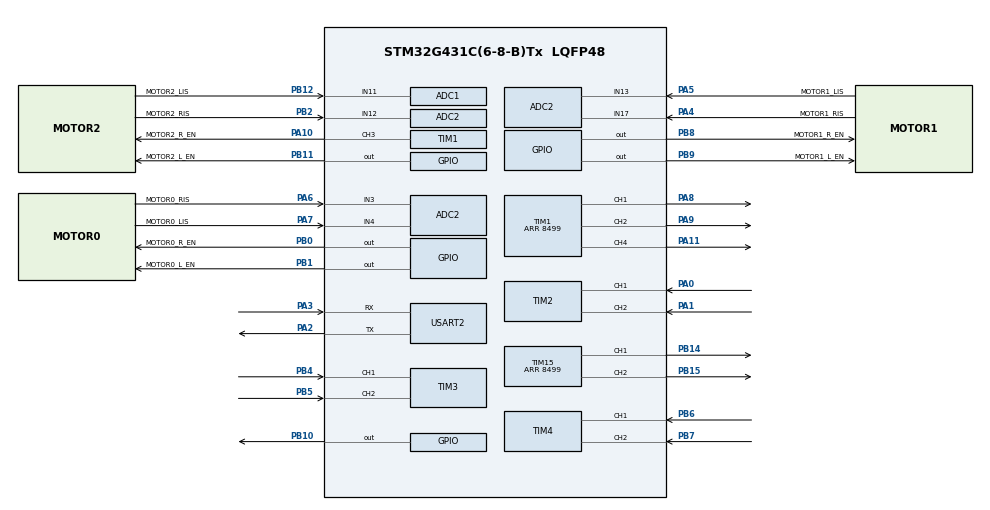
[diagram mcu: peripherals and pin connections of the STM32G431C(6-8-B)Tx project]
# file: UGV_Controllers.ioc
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ADC1.Channel-0\#ChannelRegularConversion=ADC_CHANNEL_11
ADC1.NbrOfConversionFlag=1
ADC1.OffsetNumber-0\#ChannelRegularConversion=ADC_OFFSET_NONE
ADC1.Rank-0\#ChannelRegularConversion=1
ADC1.SamplingTime-0\#ChannelRegularConversion=ADC_SAMPLETIME_2CYCLES_5
ADC1.master=1
ADC2.Channel-0\#ChannelRegularConversion=ADC_CHANNEL_3
ADC2.Channel-1\#ChannelRegularConversion=ADC_CHANNEL_4
ADC2.Channel-2\#ChannelRegularConversion=ADC_CHANNEL_12
ADC2.Channel-3\#ChannelRegularConversion=ADC_CHANNEL_13
ADC2.Channel-4\#ChannelRegularConversion=ADC_CHANNEL_17
ADC2.NbrOfConversion=5
ADC2.NbrOfConversionFlag=1
ADC2.OffsetNumber-0\#ChannelRegularConversion=ADC_OFFSET_NONE
ADC2.OffsetNumber-1\#ChannelRegularConversion=ADC_OFFSET_NONE
ADC2.OffsetNumber-2\#ChannelRegularConversion=ADC_OFFSET_NONE
ADC2.OffsetNumber-3\#ChannelRegularConversion=ADC_OFFSET_NONE
ADC2.OffsetNumber-4\#ChannelRegularConversion=ADC_OFFSET_NONE
ADC2.Rank-0\#ChannelRegularConversion=1
ADC2.Rank-1\#ChannelRegularConversion=2
ADC2.Rank-2\#ChannelRegularConversion=3
ADC2.Rank-3\#ChannelRegularConversion=4
ADC2.Rank-4\#ChannelRegularConversion=5
ADC2.SamplingTime-0\#ChannelRegularConversion=ADC_SAMPLETIME_2CYCLES_5
ADC2.SamplingTime-1\#ChannelRegularConversion=ADC_SAMPLETIME_2CYCLES_5
ADC2.SamplingTime-2\#ChannelRegularConversion=ADC_SAMPLETIME_2CYCLES_5
ADC2.SamplingTime-3\#ChannelRegularConversion=ADC_SAMPLETIME_2CYCLES_5
ADC2.SamplingTime-4\#ChannelRegularConversion=ADC_SAMPLETIME_2CYCLES_5
Mcu.Family=STM32G4
Mcu.Name=STM32G431C(6-8-B)Tx
Mcu.Package=LQFP48
NVIC.PriorityGroup=NVIC_PRIORITYGROUP_4
NVIC.USART2_IRQn=true\:5\:0\:false\:false\:true\:false\:true\:false
PA0.Signal=S_TIM2_CH1
PA1.Signal=S_TIM2_CH2
PA10.GPIO_Label=MOTOR2_R_EN
PA10.Signal=S_TIM1_CH3
PA11.Signal=S_TIM1_CH4
PA2.Mode=Asynchronous
PA2.Signal=USART2_TX
PA3.Mode=Asynchronous
PA3.Signal=USART2_RX
PA4.GPIO_Label=MOTOR1_RIS
PA4.Mode=IN17-Single-Ended
PA4.Signal=ADC2_IN17
PA5.GPIO_Label=MOTOR1_LIS
PA5.Mode=IN13-Single-Ended
PA5.Signal=ADC2_IN13
PA6.GPIO_Label=MOTOR0_RIS
PA6.Mode=IN3-Single-Ended
PA6.Signal=ADC2_IN3
PA7.GPIO_Label=MOTOR0_LIS
PA7.Mode=IN4-Single-Ended
PA7.Signal=ADC2_IN4
PA8.Signal=S_TIM1_CH1
PA9.Signal=S_TIM1_CH2
PB0.GPIO_Label=MOTOR0_R_EN
PB0.Signal=GPIO_Output
PB1.GPIO_Label=MOTOR0_L_EN
PB1.Signal=GPIO_Output
PB10.Signal=GPIO_Output
PB11.GPIO_Label=MOTOR2_L_EN
PB11.Signal=GPIO_Output
PB12.GPIO_Label=MOTOR2_LIS
PB12.Mode=IN11-Single-Ended
PB12.Signal=ADC1_IN11
PB14.Signal=S_TIM15_CH1
PB15.Signal=S_TIM15_CH2
PB2.GPIO_Label=MOTOR2_RIS
PB2.Mode=IN12-Single-Ended
PB2.Signal=ADC2_IN12
PB4.Signal=S_TIM3_CH1
PB5.Signal=S_TIM3_CH2
PB6.Signal=S_TIM4_CH1
PB7.Signal=S_TIM4_CH2
PB8-BOOT0.GPIO_Label=MOTOR1_R_EN
PB8-BOOT0.Signal=GPIO_Output
PB9.GPIO_Label=MOTOR1_L_EN
PB9.Signal=GPIO_Output
ProjectManager.HeapSize=0x200
ProjectManager.StackSize=0x400
ProjectManager.TargetToolchain=CMake
RCC.ADC12Freq_Value=170000000
RCC.AHBFreq_Value=170000000
RCC.APB1Freq_Value=170000000
RCC.APB1TimFreq_Value=170000000
RCC.APB2Freq_Value=170000000
RCC.APB2TimFreq_Value=170000000
RCC.CortexFreq_Value=170000000
RCC.EXTERNAL_CLOCK_VALUE=12288000
RCC.HCLKFreq_Value=170000000
RCC.HSE_VALUE=8000000
RCC.HSI48_VALUE=48000000
RCC.HSI_VALUE=16000000
RCC.LSE_VALUE=32768
RCC.PLLM=RCC_PLLM_DIV4
RCC.PLLN=85
RCC.PLLP=RCC_PLLP_DIV2
RCC.SYSCLKFreq_VALUE=170000000
RCC.SYSCLKSource=RCC_SYSCLKSOURCE_PLLCLK
RCC.USBFreq_Value=170000000
RCC.VCOOutputFreq_Value=340000000
SH.S_TIM15_CH1.0=TIM15_CH1,PWM Generation1 CH1
SH.S_TIM15_CH2.0=TIM15_CH2,PWM Generation2 CH2
SH.S_TIM1_CH1.0=TIM1_CH1,PWM Generation1 CH1
SH.S_TIM1_CH2.0=TIM1_CH2,PWM Generation2 CH2
SH.S_TIM1_CH3.0=TIM1_CH3,PWM Generation3 CH3
SH.S_TIM1_CH4.0=TIM1_CH4,PWM Generation4 CH4
SH.S_TIM2_CH1.0=TIM2_CH1,Encoder_Interface
SH.S_TIM2_CH2.0=TIM2_CH2,Encoder_Interface
SH.S_TIM3_CH1.0=TIM3_CH1,Encoder_Interface
SH.S_TIM3_CH2.0=TIM3_CH2,Encoder_Interface
SH.S_TIM4_CH1.0=TIM4_CH1,Encoder_Interface
SH.S_TIM4_CH2.0=TIM4_CH2,Encoder_Interface
TIM1.Channel-PWM\ Generation1\ CH1=TIM_CHANNEL_1
TIM1.Channel-PWM\ Generation2\ CH2=TIM_CHANNEL_2
TIM1.Channel-PWM\ Generation3\ CH3=TIM_CHANNEL_3
TIM1.Channel-PWM\ Generation4\ CH4=TIM_CHANNEL_4
TIM1.PeriodNoDither=8499
TIM15.Channel-PWM\ Generation1\ CH1=TIM_CHANNEL_1
TIM15.Channel-PWM\ Generation2\ CH2=TIM_CHANNEL_2
TIM15.PeriodNoDither=8499
TIM2.EncoderMode=TIM_ENCODERMODE_TI12
TIM3.EncoderMode=TIM_ENCODERMODE_TI12
TIM4.EncoderMode=TIM_ENCODERMODE_TI12
USART2.VirtualMode-Asynchronous=VM_ASYNC
VP_IWDG_VS_IWDG.Mode=IWDG_Activate
VP_SYS_VS_DBSignals.Mode=DisableDeadBatterySignals
VP_TIM15_VS_ClockSourceINT.Mode=Internal
VP_TIM1_VS_ClockSourceINT.Mode=Internal
VP_TIM6_VS_ClockSourceINT.Mode=Enable_Timer
board=custom

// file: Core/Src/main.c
/* USER CODE BEGIN Header */
/**
  ******************************************************************************
  * @file           : main.c
  * @brief          : Main program body
  ******************************************************************************
  * @attention
  *
  * Copyright (c) 2026 STMicroelectronics.
  * All rights reserved.
  *
  * This software is licensed under terms that can be found in the LICENSE file
  * in the root directory of this software component.
  * If no LICENSE file comes with this software, it is provided AS-IS.
  *
  ******************************************************************************
  */
/* USER CODE END Header */
#include "main.h"

/* USER CODE BEGIN Includes */
#include "app_main.h"
/* USER CODE END Includes */

ADC_HandleTypeDef hadc1;
ADC_HandleTypeDef hadc2;

IWDG_HandleTypeDef hiwdg;

TIM_HandleTypeDef htim1;
TIM_HandleTypeDef htim2;
TIM_HandleTypeDef htim3;
TIM_HandleTypeDef htim4;
TIM_HandleTypeDef htim6;
TIM_HandleTypeDef htim15;

UART_HandleTypeDef huart2;

void SystemClock_Config(void);
static void MX_GPIO_Init(void);
static void MX_TIM6_Init(void);
static void MX_ADC2_Init(void);
static void MX_TIM1_Init(void);
static void MX_IWDG_Init(void);
static void MX_TIM2_Init(void);
static void MX_TIM3_Init(void);
static void MX_TIM4_Init(void);
static void MX_TIM15_Init(void);
static void MX_USART2_UART_Init(void);
static void MX_ADC1_Init(void);

int main(void)
{

  /* MCU Configuration--------------------------------------------------------*/

  /* Reset of all peripherals, Initializes the Flash interface and the Systick. */
  HAL_Init();

  /* Configure the system clock */
  SystemClock_Config();

  /* Initialize all configured peripherals */
  MX_GPIO_Init();
  MX_TIM6_Init();
  MX_ADC2_Init();
  MX_TIM1_Init();
  MX_IWDG_Init();
  MX_TIM2_Init();
  MX_TIM3_Init();
  MX_TIM4_Init();
  MX_TIM15_Init();
  MX_USART2_UART_Init();
  MX_ADC1_Init();
  /* USER CODE BEGIN 2 */
  app_main_init();
  /* USER CODE END 2 */

  /* Infinite loop */
  /* USER CODE BEGIN WHILE */
  while (1)
  {
    app_main_run();
    /* USER CODE END WHILE */

  }
}

void SystemClock_Config(void)
{
  RCC_OscInitTypeDef RCC_OscInitStruct = {0};
  RCC_ClkInitTypeDef RCC_ClkInitStruct = {0};

  /** Configure the main internal regulator output voltage
  */
  HAL_PWREx_ControlVoltageScaling(PWR_REGULATOR_VOLTAGE_SCALE1);

  /** Initializes the RCC Oscillators according to the specified parameters
  * in the RCC_OscInitTypeDef structure.
  */
  RCC_OscInitStruct.OscillatorType = RCC_OSCILLATORTYPE_HSI|RCC_OSCILLATORTYPE_LSI;
  RCC_OscInitStruct.HSIState = RCC_HSI_ON;
  RCC_OscInitStruct.HSICalibrationValue = RCC_HSICALIBRATION_DEFAULT;
  RCC_OscInitStruct.LSIState = RCC_LSI_ON;
  RCC_OscInitStruct.PLL.PLLState = RCC_PLL_NONE;
  if (HAL_RCC_OscConfig(&RCC_OscInitStruct) != HAL_OK)
  {
    Error_Handler();
  }

  /** Initializes the CPU, AHB and APB buses clocks
  */
  RCC_ClkInitStruct.ClockType = RCC_CLOCKTYPE_HCLK|RCC_CLOCKTYPE_SYSCLK
                              |RCC_CLOCKTYPE_PCLK1|RCC_CLOCKTYPE_PCLK2;
  RCC_ClkInitStruct.SYSCLKSource = RCC_SYSCLKSOURCE_HSI;
  RCC_ClkInitStruct.AHBCLKDivider = RCC_SYSCLK_DIV1;
  RCC_ClkInitStruct.APB1CLKDivider = RCC_HCLK_DIV1;
  RCC_ClkInitStruct.APB2CLKDivider = RCC_HCLK_DIV1;

  if (HAL_RCC_ClockConfig(&RCC_ClkInitStruct, FLASH_LATENCY_0) != HAL_OK)
  {
    Error_Handler();
  }
}

static void MX_ADC1_Init(void)
{

  ADC_MultiModeTypeDef multimode = {0};
  ADC_ChannelConfTypeDef sConfig = {0};

  /** Common config
  */
  hadc1.Instance = ADC1;
  hadc1.Init.ClockPrescaler = ADC_CLOCK_SYNC_PCLK_DIV2;
  hadc1.Init.Resolution = ADC_RESOLUTION_12B;
  hadc1.Init.DataAlign = ADC_DATAALIGN_RIGHT;
  hadc1.Init.GainCompensation = 0;
  hadc1.Init.ScanConvMode = ADC_SCAN_DISABLE;
  hadc1.Init.EOCSelection = ADC_EOC_SINGLE_CONV;
  hadc1.Init.LowPowerAutoWait = DISABLE;
  hadc1.Init.ContinuousConvMode = DISABLE;
  hadc1.Init.NbrOfConversion = 1;
  hadc1.Init.DiscontinuousConvMode = DISABLE;
  hadc1.Init.ExternalTrigConv = ADC_SOFTWARE_START;
  hadc1.Init.ExternalTrigConvEdge = ADC_EXTERNALTRIGCONVEDGE_NONE;
  hadc1.Init.DMAContinuousRequests = DISABLE;
  hadc1.Init.Overrun = ADC_OVR_DATA_PRESERVED;
  hadc1.Init.OversamplingMode = DISABLE;
  if (HAL_ADC_Init(&hadc1) != HAL_OK)
  {
    Error_Handler();
  }

  /** Configure the ADC multi-mode
  */
  multimode.Mode = ADC_MODE_INDEPENDENT;
  if (HAL_ADCEx_MultiModeConfigChannel(&hadc1, &multimode) != HAL_OK)
  {
    Error_Handler();
  }

  /** Configure Regular Channel
  */
  sConfig.Channel = ADC_CHANNEL_11;
  sConfig.Rank = ADC_REGULAR_RANK_1;
  sConfig.SamplingTime = ADC_SAMPLETIME_2CYCLES_5;
  sConfig.SingleDiff = ADC_SINGLE_ENDED;
  sConfig.OffsetNumber = ADC_OFFSET_NONE;
  sConfig.Offset = 0;
  if (HAL_ADC_ConfigChannel(&hadc1, &sConfig) != HAL_OK)
  {
    Error_Handler();
  }

}

static void MX_ADC2_Init(void)
{

  ADC_ChannelConfTypeDef sConfig = {0};

  /** Common config
  */
  hadc2.Instance = ADC2;
  hadc2.Init.ClockPrescaler = ADC_CLOCK_SYNC_PCLK_DIV2;
  hadc2.Init.Resolution = ADC_RESOLUTION_12B;
  hadc2.Init.DataAlign = ADC_DATAALIGN_RIGHT;
  hadc2.Init.GainCompensation = 0;
  hadc2.Init.ScanConvMode = ADC_SCAN_ENABLE;
  hadc2.Init.EOCSelection = ADC_EOC_SINGLE_CONV;
  hadc2.Init.LowPowerAutoWait = DISABLE;
  hadc2.Init.ContinuousConvMode = DISABLE;
  hadc2.Init.NbrOfConversion = 5;
  hadc2.Init.DiscontinuousConvMode = DISABLE;
  hadc2.Init.ExternalTrigConv = ADC_SOFTWARE_START;
  hadc2.Init.ExternalTrigConvEdge = ADC_EXTERNALTRIGCONVEDGE_NONE;
  hadc2.Init.DMAContinuousRequests = DISABLE;
  hadc2.Init.Overrun = ADC_OVR_DATA_PRESERVED;
  hadc2.Init.OversamplingMode = DISABLE;
  if (HAL_ADC_Init(&hadc2) != HAL_OK)
  {
    Error_Handler();
  }

  /** Configure Regular Channel
  */
  sConfig.Channel = ADC_CHANNEL_3;
  sConfig.Rank = ADC_REGULAR_RANK_1;
  sConfig.SamplingTime = ADC_SAMPLETIME_2CYCLES_5;
  sConfig.SingleDiff = ADC_SINGLE_ENDED;
  sConfig.OffsetNumber = ADC_OFFSET_NONE;
  sConfig.Offset = 0;
  if (HAL_ADC_ConfigChannel(&hadc2, &sConfig) != HAL_OK)
  {
    Error_Handler();
  }

  /** Configure Regular Channel
  */
  sConfig.Channel = ADC_CHANNEL_4;
  sConfig.Rank = ADC_REGULAR_RANK_2;
  if (HAL_ADC_ConfigChannel(&hadc2, &sConfig) != HAL_OK)
  {
    Error_Handler();
  }

  /** Configure Regular Channel
  */
  sConfig.Channel = ADC_CHANNEL_12;
  sConfig.Rank = ADC_REGULAR_RANK_3;
  if (HAL_ADC_ConfigChannel(&hadc2, &sConfig) != HAL_OK)
  {
    Error_Handler();
  }

  /** Configure Regular Channel
  */
  sConfig.Channel = ADC_CHANNEL_13;
  sConfig.Rank = ADC_REGULAR_RANK_4;
  if (HAL_ADC_ConfigChannel(&hadc2, &sConfig) != HAL_OK)
  {
    Error_Handler();
  }

  /** Configure Regular Channel
  */
  sConfig.Channel = ADC_CHANNEL_17;
  sConfig.Rank = ADC_REGULAR_RANK_5;
  if (HAL_ADC_ConfigChannel(&hadc2, &sConfig) != HAL_OK)
  {
    Error_Handler();
  }

}

static void MX_IWDG_Init(void)
{

  hiwdg.Instance = IWDG;
  hiwdg.Init.Prescaler = IWDG_PRESCALER_4;
  hiwdg.Init.Window = 4095;
  hiwdg.Init.Reload = 4095;
  if (HAL_IWDG_Init(&hiwdg) != HAL_OK)
  {
    Error_Handler();
  }

}

static void MX_TIM1_Init(void)
{

  TIM_ClockConfigTypeDef sClockSourceConfig = {0};
  TIM_MasterConfigTypeDef sMasterConfig = {0};
  TIM_OC_InitTypeDef sConfigOC = {0};
  TIM_BreakDeadTimeConfigTypeDef sBreakDeadTimeConfig = {0};

  htim1.Instance = TIM1;
  htim1.Init.Prescaler = 0;
  htim1.Init.CounterMode = TIM_COUNTERMODE_UP;
  htim1.Init.Period = 799;
  htim1.Init.ClockDivision = TIM_CLOCKDIVISION_DIV1;
  htim1.Init.RepetitionCounter = 0;
  htim1.Init.AutoReloadPreload = TIM_AUTORELOAD_PRELOAD_DISABLE;
  if (HAL_TIM_Base_Init(&htim1) != HAL_OK)
  {
    Error_Handler();
  }
  sClockSourceConfig.ClockSource = TIM_CLOCKSOURCE_INTERNAL;
  if (HAL_TIM_ConfigClockSource(&htim1, &sClockSourceConfig) != HAL_OK)
  {
    Error_Handler();
  }
  if (HAL_TIM_PWM_Init(&htim1) != HAL_OK)
  {
    Error_Handler();
  }
  sMasterConfig.MasterOutputTrigger = TIM_TRGO_RESET;
  sMasterConfig.MasterOutputTrigger2 = TIM_TRGO2_RESET;
  sMasterConfig.MasterSlaveMode = TIM_MASTERSLAVEMODE_DISABLE;
  if (HAL_TIMEx_MasterConfigSynchronization(&htim1, &sMasterConfig) != HAL_OK)
  {
    Error_Handler();
  }
  sConfigOC.OCMode = TIM_OCMODE_PWM1;
  sConfigOC.Pulse = 0;
  sConfigOC.OCPolarity = TIM_OCPOLARITY_HIGH;
  sConfigOC.OCNPolarity = TIM_OCNPOLARITY_HIGH;
  sConfigOC.OCFastMode = TIM_OCFAST_DISABLE;
  sConfigOC.OCIdleState = TIM_OCIDLESTATE_RESET;
  sConfigOC.OCNIdleState = TIM_OCNIDLESTATE_RESET;
  if (HAL_TIM_PWM_ConfigChannel(&htim1, &sConfigOC, TIM_CHANNEL_1) != HAL_OK)
  {
    Error_Handler();
  }
  if (HAL_TIM_PWM_ConfigChannel(&htim1, &sConfigOC, TIM_CHANNEL_2) != HAL_OK)
  {
    Error_Handler();
  }
  if (HAL_TIM_PWM_ConfigChannel(&htim1, &sConfigOC, TIM_CHANNEL_3) != HAL_OK)
  {
    Error_Handler();
  }
  if (HAL_TIM_PWM_ConfigChannel(&htim1, &sConfigOC, TIM_CHANNEL_4) != HAL_OK)
  {
    Error_Handler();
  }
  sBreakDeadTimeConfig.OffStateRunMode = TIM_OSSR_DISABLE;
  sBreakDeadTimeConfig.OffStateIDLEMode = TIM_OSSI_DISABLE;
  sBreakDeadTimeConfig.LockLevel = TIM_LOCKLEVEL_OFF;
  sBreakDeadTimeConfig.DeadTime = 0;
  sBreakDeadTimeConfig.BreakState = TIM_BREAK_DISABLE;
  sBreakDeadTimeConfig.BreakPolarity = TIM_BREAKPOLARITY_HIGH;
  sBreakDeadTimeConfig.BreakFilter = 0;
  sBreakDeadTimeConfig.BreakAFMode = TIM_BREAK_AFMODE_INPUT;
  sBreakDeadTimeConfig.Break2State = TIM_BREAK2_DISABLE;
  sBreakDeadTimeConfig.Break2Polarity = TIM_BREAK2POLARITY_HIGH;
  sBreakDeadTimeConfig.Break2Filter = 0;
  sBreakDeadTimeConfig.Break2AFMode = TIM_BREAK_AFMODE_INPUT;
  sBreakDeadTimeConfig.AutomaticOutput = TIM_AUTOMATICOUTPUT_DISABLE;
  if (HAL_TIMEx_ConfigBreakDeadTime(&htim1, &sBreakDeadTimeConfig) != HAL_OK)
  {
    Error_Handler();
  }
  HAL_TIM_MspPostInit(&htim1);

}

static void MX_TIM2_Init(void)
{

  TIM_Encoder_InitTypeDef sConfig = {0};
  TIM_MasterConfigTypeDef sMasterConfig = {0};

  htim2.Instance = TIM2;
  htim2.Init.Prescaler = 0;
  htim2.Init.CounterMode = TIM_COUNTERMODE_UP;
  htim2.Init.Period = 4294967295;
  htim2.Init.ClockDivision = TIM_CLOCKDIVISION_DIV1;
  htim2.Init.AutoReloadPreload = TIM_AUTORELOAD_PRELOAD_DISABLE;
  sConfig.EncoderMode = TIM_ENCODERMODE_TI12;
  sConfig.IC1Polarity = TIM_ICPOLARITY_RISING;
  sConfig.IC1Selection = TIM_ICSELECTION_DIRECTTI;
  sConfig.IC1Prescaler = TIM_ICPSC_DIV1;
  sConfig.IC1Filter = 0;
  sConfig.IC2Polarity = TIM_ICPOLARITY_RISING;
  sConfig.IC2Selection = TIM_ICSELECTION_DIRECTTI;
  sConfig.IC2Prescaler = TIM_ICPSC_DIV1;
  sConfig.IC2Filter = 0;
  if (HAL_TIM_Encoder_Init(&htim2, &sConfig) != HAL_OK)
  {
    Error_Handler();
  }
  sMasterConfig.MasterOutputTrigger = TIM_TRGO_RESET;
  sMasterConfig.MasterSlaveMode = TIM_MASTERSLAVEMODE_DISABLE;
  if (HAL_TIMEx_MasterConfigSynchronization(&htim2, &sMasterConfig) != HAL_OK)
  {
    Error_Handler();
  }

}

static void MX_TIM3_Init(void)
{

  TIM_Encoder_InitTypeDef sConfig = {0};
  TIM_MasterConfigTypeDef sMasterConfig = {0};

  htim3.Instance = TIM3;
  htim3.Init.Prescaler = 0;
  htim3.Init.CounterMode = TIM_COUNTERMODE_UP;
  htim3.Init.Period = 65535;
  htim3.Init.ClockDivision = TIM_CLOCKDIVISION_DIV1;
  htim3.Init.AutoReloadPreload = TIM_AUTORELOAD_PRELOAD_DISABLE;
  sConfig.EncoderMode = TIM_ENCODERMODE_TI12;
  sConfig.IC1Polarity = TIM_ICPOLARITY_RISING;
  sConfig.IC1Selection = TIM_ICSELECTION_DIRECTTI;
  sConfig.IC1Prescaler = TIM_ICPSC_DIV1;
  sConfig.IC1Filter = 0;
  sConfig.IC2Polarity = TIM_ICPOLARITY_RISING;
  sConfig.IC2Selection = TIM_ICSELECTION_DIRECTTI;
  sConfig.IC2Prescaler = TIM_ICPSC_DIV1;
  sConfig.IC2Filter = 0;
  if (HAL_TIM_Encoder_Init(&htim3, &sConfig) != HAL_OK)
  {
    Error_Handler();
  }
  sMasterConfig.MasterOutputTrigger = TIM_TRGO_RESET;
  sMasterConfig.MasterSlaveMode = TIM_MASTERSLAVEMODE_DISABLE;
  if (HAL_TIMEx_MasterConfigSynchronization(&htim3, &sMasterConfig) != HAL_OK)
  {
    Error_Handler();
  }

}

static void MX_TIM4_Init(void)
{

  TIM_Encoder_InitTypeDef sConfig = {0};
  TIM_MasterConfigTypeDef sMasterConfig = {0};

  htim4.Instance = TIM4;
  htim4.Init.Prescaler = 0;
  htim4.Init.CounterMode = TIM_COUNTERMODE_UP;
  htim4.Init.Period = 65535;
  htim4.Init.ClockDivision = TIM_CLOCKDIVISION_DIV1;
  htim4.Init.AutoReloadPreload = TIM_AUTORELOAD_PRELOAD_DISABLE;
  sConfig.EncoderMode = TIM_ENCODERMODE_TI12;
  sConfig.IC1Polarity = TIM_ICPOLARITY_RISING;
  sConfig.IC1Selection = TIM_ICSELECTION_DIRECTTI;
  sConfig.IC1Prescaler = TIM_ICPSC_DIV1;
  sConfig.IC1Filter = 0;
  sConfig.IC2Polarity = TIM_ICPOLARITY_RISING;
  sConfig.IC2Selection = TIM_ICSELECTION_DIRECTTI;
  sConfig.IC2Prescaler = TIM_ICPSC_DIV1;
  sConfig.IC2Filter = 0;
  if (HAL_TIM_Encoder_Init(&htim4, &sConfig) != HAL_OK)
  {
    Error_Handler();
  }
  sMasterConfig.MasterOutputTrigger = TIM_TRGO_RESET;
  sMasterConfig.MasterSlaveMode = TIM_MASTERSLAVEMODE_DISABLE;
  if (HAL_TIMEx_MasterConfigSynchronization(&htim4, &sMasterConfig) != HAL_OK)
  {
    Error_Handler();
  }

}

static void MX_TIM6_Init(void)
{

  TIM_MasterConfigTypeDef sMasterConfig = {0};

  htim6.Instance = TIM6;
  htim6.Init.Prescaler = 0;
  htim6.Init.CounterMode = TIM_COUNTERMODE_UP;
  htim6.Init.Period = 65535;
  htim6.Init.AutoReloadPreload = TIM_AUTORELOAD_PRELOAD_DISABLE;
  if (HAL_TIM_Base_Init(&htim6) != HAL_OK)
  {
    Error_Handler();
  }
  sMasterConfig.MasterOutputTrigger = TIM_TRGO_RESET;
  sMasterConfig.MasterSlaveMode = TIM_MASTERSLAVEMODE_DISABLE;
  if (HAL_TIMEx_MasterConfigSynchronization(&htim6, &sMasterConfig) != HAL_OK)
  {
    Error_Handler();
  }

}

static void MX_TIM15_Init(void)
{

  TIM_ClockConfigTypeDef sClockSourceConfig = {0};
  TIM_MasterConfigTypeDef sMasterConfig = {0};
  TIM_OC_InitTypeDef sConfigOC = {0};
  TIM_BreakDeadTimeConfigTypeDef sBreakDeadTimeConfig = {0};

  htim15.Instance = TIM15;
  htim15.Init.Prescaler = 0;
  htim15.Init.CounterMode = TIM_COUNTERMODE_UP;
  htim15.Init.Period = 799;
  htim15.Init.ClockDivision = TIM_CLOCKDIVISION_DIV1;
  htim15.Init.RepetitionCounter = 0;
  htim15.Init.AutoReloadPreload = TIM_AUTORELOAD_PRELOAD_DISABLE;
  if (HAL_TIM_Base_Init(&htim15) != HAL_OK)
  {
    Error_Handler();
  }
  sClockSourceConfig.ClockSource = TIM_CLOCKSOURCE_INTERNAL;
  if (HAL_TIM_ConfigClockSource(&htim15, &sClockSourceConfig) != HAL_OK)
  {
    Error_Handler();
  }
  if (HAL_TIM_PWM_Init(&htim15) != HAL_OK)
  {
    Error_Handler();
  }
  sMasterConfig.MasterOutputTrigger = TIM_TRGO_RESET;
  sMasterConfig.MasterSlaveMode = TIM_MASTERSLAVEMODE_DISABLE;
  if (HAL_TIMEx_MasterConfigSynchronization(&htim15, &sMasterConfig) != HAL_OK)
  {
    Error_Handler();
  }
  sConfigOC.OCMode = TIM_OCMODE_PWM1;
  sConfigOC.Pulse = 0;
  sConfigOC.OCPolarity = TIM_OCPOLARITY_HIGH;
  sConfigOC.OCNPolarity = TIM_OCNPOLARITY_HIGH;
  sConfigOC.OCFastMode = TIM_OCFAST_DISABLE;
  sConfigOC.OCIdleState = TIM_OCIDLESTATE_RESET;
  sConfigOC.OCNIdleState = TIM_OCNIDLESTATE_RESET;
  if (HAL_TIM_PWM_ConfigChannel(&htim15, &sConfigOC, TIM_CHANNEL_1) != HAL_OK)
  {
    Error_Handler();
  }
  if (HAL_TIM_PWM_ConfigChannel(&htim15, &sConfigOC, TIM_CHANNEL_2) != HAL_OK)
  {
    Error_Handler();
  }
  sBreakDeadTimeConfig.OffStateRunMode = TIM_OSSR_DISABLE;
  sBreakDeadTimeConfig.OffStateIDLEMode = TIM_OSSI_DISABLE;
  sBreakDeadTimeConfig.LockLevel = TIM_LOCKLEVEL_OFF;
  sBreakDeadTimeConfig.DeadTime = 0;
  sBreakDeadTimeConfig.BreakState = TIM_BREAK_DISABLE;
  sBreakDeadTimeConfig.BreakPolarity = TIM_BREAKPOLARITY_HIGH;
  sBreakDeadTimeConfig.BreakFilter = 0;
  sBreakDeadTimeConfig.AutomaticOutput = TIM_AUTOMATICOUTPUT_DISABLE;
  if (HAL_TIMEx_ConfigBreakDeadTime(&htim15, &sBreakDeadTimeConfig) != HAL_OK)
  {
    Error_Handler();
  }
  HAL_TIM_MspPostInit(&htim15);

}

static void MX_USART2_UART_Init(void)
{

  huart2.Instance = USART2;
  huart2.Init.BaudRate = 115200;
  huart2.Init.WordLength = UART_WORDLENGTH_8B;
  huart2.Init.StopBits = UART_STOPBITS_1;
  huart2.Init.Parity = UART_PARITY_NONE;
  huart2.Init.Mode = UART_MODE_TX_RX;
  huart2.Init.HwFlowCtl = UART_HWCONTROL_NONE;
  huart2.Init.OverSampling = UART_OVERSAMPLING_16;
  huart2.Init.OneBitSampling = UART_ONE_BIT_SAMPLE_DISABLE;
  huart2.Init.ClockPrescaler = UART_PRESCALER_DIV1;
  huart2.AdvancedInit.AdvFeatureInit = UART_ADVFEATURE_NO_INIT;
  if (HAL_UART_Init(&huart2) != HAL_OK)
  {
    Error_Handler();
  }
  if (HAL_UARTEx_SetTxFifoThreshold(&huart2, UART_TXFIFO_THRESHOLD_1_8) != HAL_OK)
  {
    Error_Handler();
  }
  if (HAL_UARTEx_SetRxFifoThreshold(&huart2, UART_RXFIFO_THRESHOLD_1_8) != HAL_OK)
  {
    Error_Handler();
  }
  if (HAL_UARTEx_DisableFifoMode(&huart2) != HAL_OK)
  {
    Error_Handler();
  }

}

static void MX_GPIO_Init(void)
{
  GPIO_InitTypeDef GPIO_InitStruct = {0};

  /* GPIO Ports Clock Enable */
  __HAL_RCC_GPIOA_CLK_ENABLE();
  __HAL_RCC_GPIOB_CLK_ENABLE();

  /*Configure GPIO pin Output Level */
  HAL_GPIO_WritePin(GPIOB, MOTOR0_R_EN_Pin|MOTOR0_L_EN_Pin|GPIO_PIN_10|MOTOR2_L_EN_Pin
                          |MOTOR1_R_EN_Pin|MOTOR1_L_EN_Pin, GPIO_PIN_RESET);

  /*Configure GPIO pins : MOTOR0_R_EN_Pin MOTOR0_L_EN_Pin PB10 MOTOR2_L_EN_Pin
                           MOTOR1_R_EN_Pin MOTOR1_L_EN_Pin */
  GPIO_InitStruct.Pin = MOTOR0_R_EN_Pin|MOTOR0_L_EN_Pin|GPIO_PIN_10|MOTOR2_L_EN_Pin
                          |MOTOR1_R_EN_Pin|MOTOR1_L_EN_Pin;
  GPIO_InitStruct.Mode = GPIO_MODE_OUTPUT_PP;
  GPIO_InitStruct.Pull = GPIO_NOPULL;
  GPIO_InitStruct.Speed = GPIO_SPEED_FREQ_LOW;
  HAL_GPIO_Init(GPIOB, &GPIO_InitStruct);

}

void Error_Handler(void)
{
  __disable_irq();
  while (1)
  {
  }
}
